###############################################################
#  Generated by:      Cadence Innovus 22.17-s086_1
#  OS:                Linux x86_64(Host ID vlsiktmt)
#  Generated on:      Mon Apr  6 12:51:59 2026
#  Design:            top_axi_ram
#  Command:           write_lef_abstract -noCutObs ./outputs/top_axi_ram.lef
###############################################################

VERSION 5.8 ;

BUSBITCHARS "[]" ;
DIVIDERCHAR "/" ;

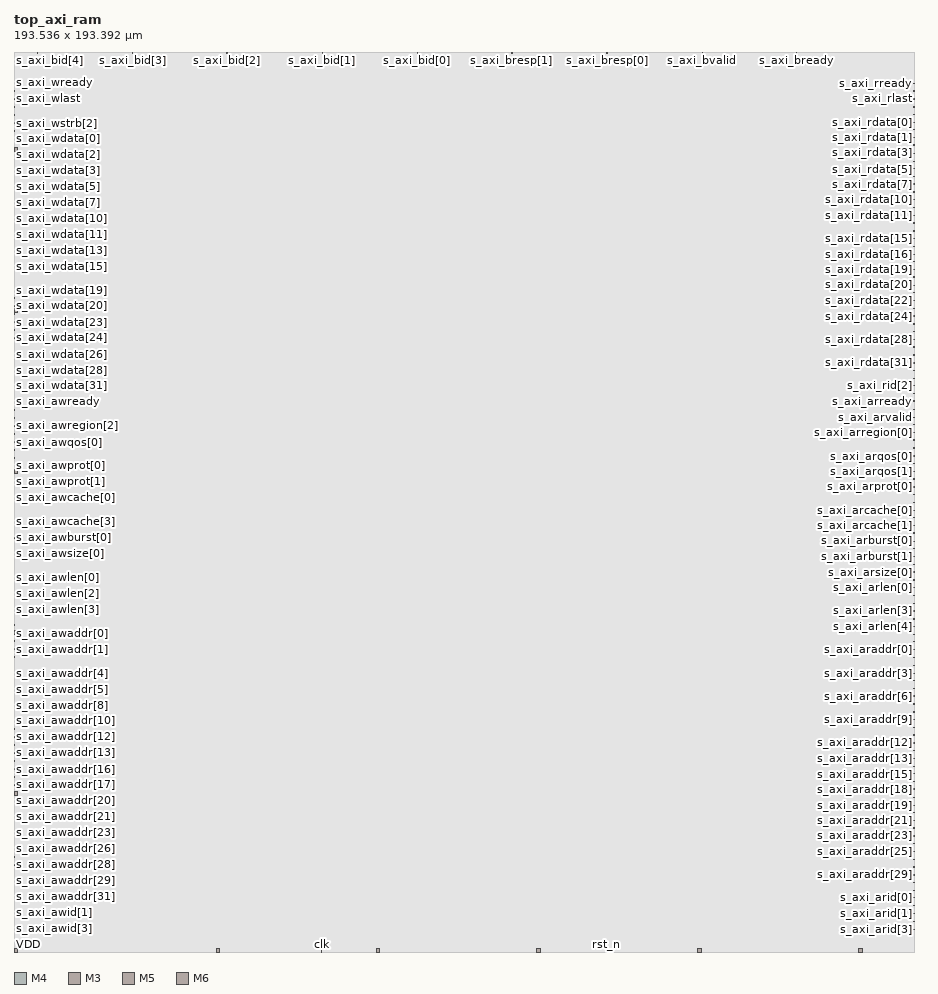
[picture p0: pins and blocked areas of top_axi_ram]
MACRO top_axi_ram
  CLASS BLOCK ;
  SIZE 193.536000 BY 193.392000 ;
  FOREIGN top_axi_ram 0.000000 0.000000 ;
  ORIGIN 0 0 ;
  SYMMETRY X Y R90 ;
  PIN clk
    DIRECTION INPUT ;
    USE SIGNAL ;
    PORT
      LAYER M4 ;
        RECT 66.048000 0.000000 66.144000 0.336000 ;
    END
  END clk
  PIN rst_n
    DIRECTION INPUT ;
    USE SIGNAL ;
    PORT
      LAYER M4 ;
        RECT 127.248000 0.000000 127.344000 0.336000 ;
    END
  END rst_n
  PIN s_axi_awid[4]
    DIRECTION INPUT ;
    USE SIGNAL ;
    PORT
      LAYER M3 ;
        RECT 0.000000 5.004000 0.148000 5.076000 ;
    END
  END s_axi_awid[4]
  PIN s_axi_awid[3]
    DIRECTION INPUT ;
    USE SIGNAL ;
    PORT
      LAYER M3 ;
        RECT 0.000000 6.732000 0.148000 6.804000 ;
    END
  END s_axi_awid[3]
  PIN s_axi_awid[2]
    DIRECTION INPUT ;
    USE SIGNAL ;
    PORT
      LAYER M3 ;
        RECT 0.000000 8.460000 0.148000 8.532000 ;
    END
  END s_axi_awid[2]
  PIN s_axi_awid[1]
    DIRECTION INPUT ;
    USE SIGNAL ;
    PORT
      LAYER M3 ;
        RECT 0.000000 10.188000 0.148000 10.260000 ;
    END
  END s_axi_awid[1]
  PIN s_axi_awid[0]
    DIRECTION INPUT ;
    USE SIGNAL ;
    PORT
      LAYER M3 ;
        RECT 0.000000 11.916000 0.148000 11.988000 ;
    END
  END s_axi_awid[0]
  PIN s_axi_awaddr[31]
    DIRECTION INPUT ;
    USE SIGNAL ;
    PORT
      LAYER M3 ;
        RECT 0.000000 13.644000 0.148000 13.716000 ;
    END
  END s_axi_awaddr[31]
  PIN s_axi_awaddr[30]
    DIRECTION INPUT ;
    USE SIGNAL ;
    PORT
      LAYER M3 ;
        RECT 0.000000 15.372000 0.148000 15.444000 ;
    END
  END s_axi_awaddr[30]
  PIN s_axi_awaddr[29]
    DIRECTION INPUT ;
    USE SIGNAL ;
    PORT
      LAYER M3 ;
        RECT 0.000000 17.100000 0.148000 17.172000 ;
    END
  END s_axi_awaddr[29]
  PIN s_axi_awaddr[28]
    DIRECTION INPUT ;
    USE SIGNAL ;
    PORT
      LAYER M3 ;
        RECT 0.000000 18.684000 0.148000 18.756000 ;
    END
  END s_axi_awaddr[28]
  PIN s_axi_awaddr[27]
    DIRECTION INPUT ;
    USE SIGNAL ;
    PORT
      LAYER M3 ;
        RECT 0.000000 20.412000 0.148000 20.484000 ;
    END
  END s_axi_awaddr[27]
  PIN s_axi_awaddr[26]
    DIRECTION INPUT ;
    USE SIGNAL ;
    PORT
      LAYER M3 ;
        RECT 0.000000 22.140000 0.148000 22.212000 ;
    END
  END s_axi_awaddr[26]
  PIN s_axi_awaddr[25]
    DIRECTION INPUT ;
    USE SIGNAL ;
    PORT
      LAYER M3 ;
        RECT 0.000000 23.868000 0.148000 23.940000 ;
    END
  END s_axi_awaddr[25]
  PIN s_axi_awaddr[24]
    DIRECTION INPUT ;
    USE SIGNAL ;
    PORT
      LAYER M3 ;
        RECT 0.000000 25.596000 0.148000 25.668000 ;
    END
  END s_axi_awaddr[24]
  PIN s_axi_awaddr[23]
    DIRECTION INPUT ;
    USE SIGNAL ;
    PORT
      LAYER M3 ;
        RECT 0.000000 27.324000 0.148000 27.396000 ;
    END
  END s_axi_awaddr[23]
  PIN s_axi_awaddr[22]
    DIRECTION INPUT ;
    USE SIGNAL ;
    PORT
      LAYER M3 ;
        RECT 0.000000 29.052000 0.148000 29.124000 ;
    END
  END s_axi_awaddr[22]
  PIN s_axi_awaddr[21]
    DIRECTION INPUT ;
    USE SIGNAL ;
    PORT
      LAYER M3 ;
        RECT 0.000000 30.780000 0.148000 30.852000 ;
    END
  END s_axi_awaddr[21]
  PIN s_axi_awaddr[20]
    DIRECTION INPUT ;
    USE SIGNAL ;
    PORT
      LAYER M3 ;
        RECT 0.000000 32.508000 0.148000 32.580000 ;
    END
  END s_axi_awaddr[20]
  PIN s_axi_awaddr[19]
    DIRECTION INPUT ;
    USE SIGNAL ;
    PORT
      LAYER M3 ;
        RECT 0.000000 34.236000 0.148000 34.308000 ;
    END
  END s_axi_awaddr[19]
  PIN s_axi_awaddr[18]
    DIRECTION INPUT ;
    USE SIGNAL ;
    PORT
      LAYER M3 ;
        RECT 0.000000 35.820000 0.148000 35.892000 ;
    END
  END s_axi_awaddr[18]
  PIN s_axi_awaddr[17]
    DIRECTION INPUT ;
    USE SIGNAL ;
    PORT
      LAYER M3 ;
        RECT 0.000000 37.548000 0.148000 37.620000 ;
    END
  END s_axi_awaddr[17]
  PIN s_axi_awaddr[16]
    DIRECTION INPUT ;
    USE SIGNAL ;
    PORT
      LAYER M3 ;
        RECT 0.000000 39.276000 0.148000 39.348000 ;
    END
  END s_axi_awaddr[16]
  PIN s_axi_awaddr[15]
    DIRECTION INPUT ;
    USE SIGNAL ;
    PORT
      LAYER M3 ;
        RECT 0.000000 41.004000 0.148000 41.076000 ;
    END
  END s_axi_awaddr[15]
  PIN s_axi_awaddr[14]
    DIRECTION INPUT ;
    USE SIGNAL ;
    PORT
      LAYER M3 ;
        RECT 0.000000 42.732000 0.148000 42.804000 ;
    END
  END s_axi_awaddr[14]
  PIN s_axi_awaddr[13]
    DIRECTION INPUT ;
    USE SIGNAL ;
    PORT
      LAYER M3 ;
        RECT 0.000000 44.460000 0.148000 44.532000 ;
    END
  END s_axi_awaddr[13]
  PIN s_axi_awaddr[12]
    DIRECTION INPUT ;
    USE SIGNAL ;
    PORT
      LAYER M3 ;
        RECT 0.000000 46.188000 0.148000 46.260000 ;
    END
  END s_axi_awaddr[12]
  PIN s_axi_awaddr[11]
    DIRECTION INPUT ;
    USE SIGNAL ;
    PORT
      LAYER M3 ;
        RECT 0.000000 47.916000 0.148000 47.988000 ;
    END
  END s_axi_awaddr[11]
  PIN s_axi_awaddr[10]
    DIRECTION INPUT ;
    USE SIGNAL ;
    PORT
      LAYER M3 ;
        RECT 0.000000 49.644000 0.148000 49.716000 ;
    END
  END s_axi_awaddr[10]
  PIN s_axi_awaddr[9]
    DIRECTION INPUT ;
    USE SIGNAL ;
    PORT
      LAYER M3 ;
        RECT 0.000000 51.372000 0.148000 51.444000 ;
    END
  END s_axi_awaddr[9]
  PIN s_axi_awaddr[8]
    DIRECTION INPUT ;
    USE SIGNAL ;
    PORT
      LAYER M3 ;
        RECT 0.000000 52.956000 0.148000 53.028000 ;
    END
  END s_axi_awaddr[8]
  PIN s_axi_awaddr[7]
    DIRECTION INPUT ;
    USE SIGNAL ;
    PORT
      LAYER M3 ;
        RECT 0.000000 54.684000 0.148000 54.756000 ;
    END
  END s_axi_awaddr[7]
  PIN s_axi_awaddr[6]
    DIRECTION INPUT ;
    USE SIGNAL ;
    PORT
      LAYER M3 ;
        RECT 0.000000 56.412000 0.148000 56.484000 ;
    END
  END s_axi_awaddr[6]
  PIN s_axi_awaddr[5]
    DIRECTION INPUT ;
    USE SIGNAL ;
    PORT
      LAYER M3 ;
        RECT 0.000000 58.140000 0.148000 58.212000 ;
    END
  END s_axi_awaddr[5]
  PIN s_axi_awaddr[4]
    DIRECTION INPUT ;
    USE SIGNAL ;
    PORT
      LAYER M3 ;
        RECT 0.000000 59.868000 0.148000 59.940000 ;
    END
  END s_axi_awaddr[4]
  PIN s_axi_awaddr[3]
    DIRECTION INPUT ;
    USE SIGNAL ;
    PORT
      LAYER M3 ;
        RECT 0.000000 61.596000 0.148000 61.668000 ;
    END
  END s_axi_awaddr[3]
  PIN s_axi_awaddr[2]
    DIRECTION INPUT ;
    USE SIGNAL ;
    PORT
      LAYER M3 ;
        RECT 0.000000 63.324000 0.148000 63.396000 ;
    END
  END s_axi_awaddr[2]
  PIN s_axi_awaddr[1]
    DIRECTION INPUT ;
    USE SIGNAL ;
    PORT
      LAYER M3 ;
        RECT 0.000000 65.052000 0.148000 65.124000 ;
    END
  END s_axi_awaddr[1]
  PIN s_axi_awaddr[0]
    DIRECTION INPUT ;
    USE SIGNAL ;
    PORT
      LAYER M3 ;
        RECT 0.000000 66.780000 0.148000 66.852000 ;
    END
  END s_axi_awaddr[0]
  PIN s_axi_awlen[7]
    DIRECTION INPUT ;
    USE SIGNAL ;
    PORT
      LAYER M3 ;
        RECT 0.000000 68.508000 0.148000 68.580000 ;
    END
  END s_axi_awlen[7]
  PIN s_axi_awlen[6]
    DIRECTION INPUT ;
    USE SIGNAL ;
    PORT
      LAYER M3 ;
        RECT 0.000000 70.236000 0.148000 70.308000 ;
    END
  END s_axi_awlen[6]
  PIN s_axi_awlen[5]
    DIRECTION INPUT ;
    USE SIGNAL ;
    PORT
      LAYER M3 ;
        RECT 0.000000 71.820000 0.148000 71.892000 ;
    END
  END s_axi_awlen[5]
  PIN s_axi_awlen[4]
    DIRECTION INPUT ;
    USE SIGNAL ;
    PORT
      LAYER M3 ;
        RECT 0.000000 73.548000 0.148000 73.620000 ;
    END
  END s_axi_awlen[4]
  PIN s_axi_awlen[3]
    DIRECTION INPUT ;
    USE SIGNAL ;
    PORT
      LAYER M3 ;
        RECT 0.000000 75.276000 0.148000 75.348000 ;
    END
  END s_axi_awlen[3]
  PIN s_axi_awlen[2]
    DIRECTION INPUT ;
    USE SIGNAL ;
    PORT
      LAYER M3 ;
        RECT 0.000000 77.004000 0.148000 77.076000 ;
    END
  END s_axi_awlen[2]
  PIN s_axi_awlen[1]
    DIRECTION INPUT ;
    USE SIGNAL ;
    PORT
      LAYER M3 ;
        RECT 0.000000 78.732000 0.148000 78.804000 ;
    END
  END s_axi_awlen[1]
  PIN s_axi_awlen[0]
    DIRECTION INPUT ;
    USE SIGNAL ;
    PORT
      LAYER M3 ;
        RECT 0.000000 80.460000 0.148000 80.532000 ;
    END
  END s_axi_awlen[0]
  PIN s_axi_awsize[2]
    DIRECTION INPUT ;
    USE SIGNAL ;
    PORT
      LAYER M3 ;
        RECT 0.000000 82.188000 0.148000 82.260000 ;
    END
  END s_axi_awsize[2]
  PIN s_axi_awsize[1]
    DIRECTION INPUT ;
    USE SIGNAL ;
    PORT
      LAYER M3 ;
        RECT 0.000000 83.916000 0.148000 83.988000 ;
    END
  END s_axi_awsize[1]
  PIN s_axi_awsize[0]
    DIRECTION INPUT ;
    USE SIGNAL ;
    PORT
      LAYER M3 ;
        RECT 0.000000 85.644000 0.148000 85.716000 ;
    END
  END s_axi_awsize[0]
  PIN s_axi_awburst[1]
    DIRECTION INPUT ;
    USE SIGNAL ;
    PORT
      LAYER M3 ;
        RECT 0.000000 87.372000 0.148000 87.444000 ;
    END
  END s_axi_awburst[1]
  PIN s_axi_awburst[0]
    DIRECTION INPUT ;
    USE SIGNAL ;
    PORT
      LAYER M3 ;
        RECT 0.000000 88.956000 0.148000 89.028000 ;
    END
  END s_axi_awburst[0]
  PIN s_axi_awlock
    DIRECTION INPUT ;
    USE SIGNAL ;
    PORT
      LAYER M3 ;
        RECT 0.000000 90.684000 0.148000 90.756000 ;
    END
  END s_axi_awlock
  PIN s_axi_awcache[3]
    DIRECTION INPUT ;
    USE SIGNAL ;
    PORT
      LAYER M3 ;
        RECT 0.000000 92.412000 0.148000 92.484000 ;
    END
  END s_axi_awcache[3]
  PIN s_axi_awcache[2]
    DIRECTION INPUT ;
    USE SIGNAL ;
    PORT
      LAYER M3 ;
        RECT 0.000000 94.140000 0.148000 94.212000 ;
    END
  END s_axi_awcache[2]
  PIN s_axi_awcache[1]
    DIRECTION INPUT ;
    USE SIGNAL ;
    PORT
      LAYER M3 ;
        RECT 0.000000 95.868000 0.148000 95.940000 ;
    END
  END s_axi_awcache[1]
  PIN s_axi_awcache[0]
    DIRECTION INPUT ;
    USE SIGNAL ;
    PORT
      LAYER M3 ;
        RECT 0.000000 97.596000 0.148000 97.668000 ;
    END
  END s_axi_awcache[0]
  PIN s_axi_awprot[2]
    DIRECTION INPUT ;
    USE SIGNAL ;
    PORT
      LAYER M3 ;
        RECT 0.000000 99.324000 0.148000 99.396000 ;
    END
  END s_axi_awprot[2]
  PIN s_axi_awprot[1]
    DIRECTION INPUT ;
    USE SIGNAL ;
    PORT
      LAYER M3 ;
        RECT 0.000000 101.052000 0.148000 101.124000 ;
    END
  END s_axi_awprot[1]
  PIN s_axi_awprot[0]
    DIRECTION INPUT ;
    USE SIGNAL ;
    PORT
      LAYER M3 ;
        RECT 0.000000 102.780000 0.148000 102.852000 ;
    END
  END s_axi_awprot[0]
  PIN s_axi_awqos[3]
    DIRECTION INPUT ;
    USE SIGNAL ;
    PORT
      LAYER M3 ;
        RECT 0.000000 104.508000 0.148000 104.580000 ;
    END
  END s_axi_awqos[3]
  PIN s_axi_awqos[2]
    DIRECTION INPUT ;
    USE SIGNAL ;
    PORT
      LAYER M3 ;
        RECT 0.000000 106.092000 0.148000 106.164000 ;
    END
  END s_axi_awqos[2]
  PIN s_axi_awqos[1]
    DIRECTION INPUT ;
    USE SIGNAL ;
    PORT
      LAYER M3 ;
        RECT 0.000000 107.820000 0.148000 107.892000 ;
    END
  END s_axi_awqos[1]
  PIN s_axi_awqos[0]
    DIRECTION INPUT ;
    USE SIGNAL ;
    PORT
      LAYER M3 ;
        RECT 0.000000 109.548000 0.148000 109.620000 ;
    END
  END s_axi_awqos[0]
  PIN s_axi_awregion[3]
    DIRECTION INPUT ;
    USE SIGNAL ;
    PORT
      LAYER M3 ;
        RECT 0.000000 111.276000 0.148000 111.348000 ;
    END
  END s_axi_awregion[3]
  PIN s_axi_awregion[2]
    DIRECTION INPUT ;
    USE SIGNAL ;
    PORT
      LAYER M3 ;
        RECT 0.000000 113.004000 0.148000 113.076000 ;
    END
  END s_axi_awregion[2]
  PIN s_axi_awregion[1]
    DIRECTION INPUT ;
    USE SIGNAL ;
    PORT
      LAYER M3 ;
        RECT 0.000000 114.732000 0.148000 114.804000 ;
    END
  END s_axi_awregion[1]
  PIN s_axi_awregion[0]
    DIRECTION INPUT ;
    USE SIGNAL ;
    PORT
      LAYER M3 ;
        RECT 0.000000 116.460000 0.148000 116.532000 ;
    END
  END s_axi_awregion[0]
  PIN s_axi_awvalid
    DIRECTION INPUT ;
    USE SIGNAL ;
    PORT
      LAYER M3 ;
        RECT 0.000000 118.188000 0.148000 118.260000 ;
    END
  END s_axi_awvalid
  PIN s_axi_awready
    DIRECTION OUTPUT ;
    USE SIGNAL ;
    PORT
      LAYER M3 ;
        RECT 0.000000 119.916000 0.148000 119.988000 ;
    END
  END s_axi_awready
  PIN s_axi_wdata[31]
    DIRECTION INPUT ;
    USE SIGNAL ;
    PORT
      LAYER M3 ;
        RECT 0.000000 121.644000 0.148000 121.716000 ;
    END
  END s_axi_wdata[31]
  PIN s_axi_wdata[30]
    DIRECTION INPUT ;
    USE SIGNAL ;
    PORT
      LAYER M3 ;
        RECT 0.000000 123.228000 0.148000 123.300000 ;
    END
  END s_axi_wdata[30]
  PIN s_axi_wdata[29]
    DIRECTION INPUT ;
    USE SIGNAL ;
    PORT
      LAYER M3 ;
        RECT 0.000000 124.956000 0.148000 125.028000 ;
    END
  END s_axi_wdata[29]
  PIN s_axi_wdata[28]
    DIRECTION INPUT ;
    USE SIGNAL ;
    PORT
      LAYER M3 ;
        RECT 0.000000 126.684000 0.148000 126.756000 ;
    END
  END s_axi_wdata[28]
  PIN s_axi_wdata[27]
    DIRECTION INPUT ;
    USE SIGNAL ;
    PORT
      LAYER M3 ;
        RECT 0.000000 128.412000 0.148000 128.484000 ;
    END
  END s_axi_wdata[27]
  PIN s_axi_wdata[26]
    DIRECTION INPUT ;
    USE SIGNAL ;
    PORT
      LAYER M3 ;
        RECT 0.000000 130.140000 0.148000 130.212000 ;
    END
  END s_axi_wdata[26]
  PIN s_axi_wdata[25]
    DIRECTION INPUT ;
    USE SIGNAL ;
    PORT
      LAYER M3 ;
        RECT 0.000000 131.868000 0.148000 131.940000 ;
    END
  END s_axi_wdata[25]
  PIN s_axi_wdata[24]
    DIRECTION INPUT ;
    USE SIGNAL ;
    PORT
      LAYER M3 ;
        RECT 0.000000 133.596000 0.148000 133.668000 ;
    END
  END s_axi_wdata[24]
  PIN s_axi_wdata[23]
    DIRECTION INPUT ;
    USE SIGNAL ;
    PORT
      LAYER M3 ;
        RECT 0.000000 135.324000 0.148000 135.396000 ;
    END
  END s_axi_wdata[23]
  PIN s_axi_wdata[22]
    DIRECTION INPUT ;
    USE SIGNAL ;
    PORT
      LAYER M3 ;
        RECT 0.000000 137.052000 0.148000 137.124000 ;
    END
  END s_axi_wdata[22]
  PIN s_axi_wdata[21]
    DIRECTION INPUT ;
    USE SIGNAL ;
    PORT
      LAYER M3 ;
        RECT 0.000000 138.780000 0.148000 138.852000 ;
    END
  END s_axi_wdata[21]
  PIN s_axi_wdata[20]
    DIRECTION INPUT ;
    USE SIGNAL ;
    PORT
      LAYER M3 ;
        RECT 0.000000 140.508000 0.148000 140.580000 ;
    END
  END s_axi_wdata[20]
  PIN s_axi_wdata[19]
    DIRECTION INPUT ;
    USE SIGNAL ;
    PORT
      LAYER M3 ;
        RECT 0.000000 142.092000 0.148000 142.164000 ;
    END
  END s_axi_wdata[19]
  PIN s_axi_wdata[18]
    DIRECTION INPUT ;
    USE SIGNAL ;
    PORT
      LAYER M3 ;
        RECT 0.000000 143.820000 0.148000 143.892000 ;
    END
  END s_axi_wdata[18]
  PIN s_axi_wdata[17]
    DIRECTION INPUT ;
    USE SIGNAL ;
    PORT
      LAYER M3 ;
        RECT 0.000000 145.548000 0.148000 145.620000 ;
    END
  END s_axi_wdata[17]
  PIN s_axi_wdata[16]
    DIRECTION INPUT ;
    USE SIGNAL ;
    PORT
      LAYER M3 ;
        RECT 0.000000 147.276000 0.148000 147.348000 ;
    END
  END s_axi_wdata[16]
  PIN s_axi_wdata[15]
    DIRECTION INPUT ;
    USE SIGNAL ;
    PORT
      LAYER M3 ;
        RECT 0.000000 149.004000 0.148000 149.076000 ;
    END
  END s_axi_wdata[15]
  PIN s_axi_wdata[14]
    DIRECTION INPUT ;
    USE SIGNAL ;
    PORT
      LAYER M3 ;
        RECT 0.000000 150.732000 0.148000 150.804000 ;
    END
  END s_axi_wdata[14]
  PIN s_axi_wdata[13]
    DIRECTION INPUT ;
    USE SIGNAL ;
    PORT
      LAYER M3 ;
        RECT 0.000000 152.460000 0.148000 152.532000 ;
    END
  END s_axi_wdata[13]
  PIN s_axi_wdata[12]
    DIRECTION INPUT ;
    USE SIGNAL ;
    PORT
      LAYER M3 ;
        RECT 0.000000 154.188000 0.148000 154.260000 ;
    END
  END s_axi_wdata[12]
  PIN s_axi_wdata[11]
    DIRECTION INPUT ;
    USE SIGNAL ;
    PORT
      LAYER M3 ;
        RECT 0.000000 155.916000 0.148000 155.988000 ;
    END
  END s_axi_wdata[11]
  PIN s_axi_wdata[10]
    DIRECTION INPUT ;
    USE SIGNAL ;
    PORT
      LAYER M3 ;
        RECT 0.000000 157.644000 0.148000 157.716000 ;
    END
  END s_axi_wdata[10]
  PIN s_axi_wdata[9]
    DIRECTION INPUT ;
    USE SIGNAL ;
    PORT
      LAYER M3 ;
        RECT 0.000000 159.228000 0.148000 159.300000 ;
    END
  END s_axi_wdata[9]
  PIN s_axi_wdata[8]
    DIRECTION INPUT ;
    USE SIGNAL ;
    PORT
      LAYER M3 ;
        RECT 0.000000 160.956000 0.148000 161.028000 ;
    END
  END s_axi_wdata[8]
  PIN s_axi_wdata[7]
    DIRECTION INPUT ;
    USE SIGNAL ;
    PORT
      LAYER M3 ;
        RECT 0.000000 162.684000 0.148000 162.756000 ;
    END
  END s_axi_wdata[7]
  PIN s_axi_wdata[6]
    DIRECTION INPUT ;
    USE SIGNAL ;
    PORT
      LAYER M3 ;
        RECT 0.000000 164.412000 0.148000 164.484000 ;
    END
  END s_axi_wdata[6]
  PIN s_axi_wdata[5]
    DIRECTION INPUT ;
    USE SIGNAL ;
    PORT
      LAYER M3 ;
        RECT 0.000000 166.140000 0.148000 166.212000 ;
    END
  END s_axi_wdata[5]
  PIN s_axi_wdata[4]
    DIRECTION INPUT ;
    USE SIGNAL ;
    PORT
      LAYER M3 ;
        RECT 0.000000 167.868000 0.148000 167.940000 ;
    END
  END s_axi_wdata[4]
  PIN s_axi_wdata[3]
    DIRECTION INPUT ;
    USE SIGNAL ;
    PORT
      LAYER M3 ;
        RECT 0.000000 169.596000 0.148000 169.668000 ;
    END
  END s_axi_wdata[3]
  PIN s_axi_wdata[2]
    DIRECTION INPUT ;
    USE SIGNAL ;
    PORT
      LAYER M3 ;
        RECT 0.000000 171.324000 0.148000 171.396000 ;
    END
  END s_axi_wdata[2]
  PIN s_axi_wdata[1]
    DIRECTION INPUT ;
    USE SIGNAL ;
    PORT
      LAYER M3 ;
        RECT 0.000000 173.052000 0.148000 173.124000 ;
    END
  END s_axi_wdata[1]
  PIN s_axi_wdata[0]
    DIRECTION INPUT ;
    USE SIGNAL ;
    PORT
      LAYER M3 ;
        RECT 0.000000 174.780000 0.148000 174.852000 ;
    END
  END s_axi_wdata[0]
  PIN s_axi_wstrb[3]
    DIRECTION INPUT ;
    USE SIGNAL ;
    PORT
      LAYER M3 ;
        RECT 0.000000 176.364000 0.148000 176.436000 ;
    END
  END s_axi_wstrb[3]
  PIN s_axi_wstrb[2]
    DIRECTION INPUT ;
    USE SIGNAL ;
    PORT
      LAYER M3 ;
        RECT 0.000000 178.092000 0.148000 178.164000 ;
    END
  END s_axi_wstrb[2]
  PIN s_axi_wstrb[1]
    DIRECTION INPUT ;
    USE SIGNAL ;
    PORT
      LAYER M3 ;
        RECT 0.000000 179.820000 0.148000 179.892000 ;
    END
  END s_axi_wstrb[1]
  PIN s_axi_wstrb[0]
    DIRECTION INPUT ;
    USE SIGNAL ;
    PORT
      LAYER M3 ;
        RECT 0.000000 181.548000 0.148000 181.620000 ;
    END
  END s_axi_wstrb[0]
  PIN s_axi_wlast
    DIRECTION INPUT ;
    USE SIGNAL ;
    PORT
      LAYER M3 ;
        RECT 0.000000 183.276000 0.148000 183.348000 ;
    END
  END s_axi_wlast
  PIN s_axi_wvalid
    DIRECTION INPUT ;
    USE SIGNAL ;
    PORT
      LAYER M3 ;
        RECT 0.000000 185.004000 0.148000 185.076000 ;
    END
  END s_axi_wvalid
  PIN s_axi_wready
    DIRECTION OUTPUT ;
    USE SIGNAL ;
    PORT
      LAYER M3 ;
        RECT 0.000000 186.732000 0.148000 186.804000 ;
    END
  END s_axi_wready
  PIN s_axi_bid[4]
    DIRECTION OUTPUT ;
    USE SIGNAL ;
    PORT
      LAYER M4 ;
        RECT 4.992000 193.056000 5.088000 193.392000 ;
    END
  END s_axi_bid[4]
  PIN s_axi_bid[3]
    DIRECTION OUTPUT ;
    USE SIGNAL ;
    PORT
      LAYER M4 ;
        RECT 25.440000 193.056000 25.536000 193.392000 ;
    END
  END s_axi_bid[3]
  PIN s_axi_bid[2]
    DIRECTION OUTPUT ;
    USE SIGNAL ;
    PORT
      LAYER M4 ;
        RECT 45.744000 193.056000 45.840000 193.392000 ;
    END
  END s_axi_bid[2]
  PIN s_axi_bid[1]
    DIRECTION OUTPUT ;
    USE SIGNAL ;
    PORT
      LAYER M4 ;
        RECT 66.192000 193.056000 66.288000 193.392000 ;
    END
  END s_axi_bid[1]
  PIN s_axi_bid[0]
    DIRECTION OUTPUT ;
    USE SIGNAL ;
    PORT
      LAYER M4 ;
        RECT 86.640000 193.056000 86.736000 193.392000 ;
    END
  END s_axi_bid[0]
  PIN s_axi_bresp[1]
    DIRECTION OUTPUT ;
    USE SIGNAL ;
    PORT
      LAYER M4 ;
        RECT 106.944000 193.056000 107.040000 193.392000 ;
    END
  END s_axi_bresp[1]
  PIN s_axi_bresp[0]
    DIRECTION OUTPUT ;
    USE SIGNAL ;
    PORT
      LAYER M4 ;
        RECT 127.392000 193.056000 127.488000 193.392000 ;
    END
  END s_axi_bresp[0]
  PIN s_axi_bvalid
    DIRECTION OUTPUT ;
    USE SIGNAL ;
    PORT
      LAYER M4 ;
        RECT 147.840000 193.056000 147.936000 193.392000 ;
    END
  END s_axi_bvalid
  PIN s_axi_bready
    DIRECTION INPUT ;
    USE SIGNAL ;
    PORT
      LAYER M4 ;
        RECT 168.144000 193.056000 168.240000 193.392000 ;
    END
  END s_axi_bready
  PIN s_axi_arid[4]
    DIRECTION INPUT ;
    USE SIGNAL ;
    PORT
      LAYER M3 ;
        RECT 193.388000 4.860000 193.536000 4.932000 ;
    END
  END s_axi_arid[4]
  PIN s_axi_arid[3]
    DIRECTION INPUT ;
    USE SIGNAL ;
    PORT
      LAYER M3 ;
        RECT 193.388000 6.588000 193.536000 6.660000 ;
    END
  END s_axi_arid[3]
  PIN s_axi_arid[2]
    DIRECTION INPUT ;
    USE SIGNAL ;
    PORT
      LAYER M3 ;
        RECT 193.388000 8.172000 193.536000 8.244000 ;
    END
  END s_axi_arid[2]
  PIN s_axi_arid[1]
    DIRECTION INPUT ;
    USE SIGNAL ;
    PORT
      LAYER M3 ;
        RECT 193.388000 9.900000 193.536000 9.972000 ;
    END
  END s_axi_arid[1]
  PIN s_axi_arid[0]
    DIRECTION INPUT ;
    USE SIGNAL ;
    PORT
      LAYER M3 ;
        RECT 193.388000 11.628000 193.536000 11.700000 ;
    END
  END s_axi_arid[0]
  PIN s_axi_araddr[31]
    DIRECTION INPUT ;
    USE SIGNAL ;
    PORT
      LAYER M3 ;
        RECT 193.388000 13.212000 193.536000 13.284000 ;
    END
  END s_axi_araddr[31]
  PIN s_axi_araddr[30]
    DIRECTION INPUT ;
    USE SIGNAL ;
    PORT
      LAYER M3 ;
        RECT 193.388000 14.940000 193.536000 15.012000 ;
    END
  END s_axi_araddr[30]
  PIN s_axi_araddr[29]
    DIRECTION INPUT ;
    USE SIGNAL ;
    PORT
      LAYER M3 ;
        RECT 193.388000 16.524000 193.536000 16.596000 ;
    END
  END s_axi_araddr[29]
  PIN s_axi_araddr[28]
    DIRECTION INPUT ;
    USE SIGNAL ;
    PORT
      LAYER M3 ;
        RECT 193.388000 18.252000 193.536000 18.324000 ;
    END
  END s_axi_araddr[28]
  PIN s_axi_araddr[27]
    DIRECTION INPUT ;
    USE SIGNAL ;
    PORT
      LAYER M3 ;
        RECT 193.388000 19.836000 193.536000 19.908000 ;
    END
  END s_axi_araddr[27]
  PIN s_axi_araddr[26]
    DIRECTION INPUT ;
    USE SIGNAL ;
    PORT
      LAYER M3 ;
        RECT 193.388000 21.564000 193.536000 21.636000 ;
    END
  END s_axi_araddr[26]
  PIN s_axi_araddr[25]
    DIRECTION INPUT ;
    USE SIGNAL ;
    PORT
      LAYER M3 ;
        RECT 193.388000 23.292000 193.536000 23.364000 ;
    END
  END s_axi_araddr[25]
  PIN s_axi_araddr[24]
    DIRECTION INPUT ;
    USE SIGNAL ;
    PORT
      LAYER M3 ;
        RECT 193.388000 24.876000 193.536000 24.948000 ;
    END
  END s_axi_araddr[24]
  PIN s_axi_araddr[23]
    DIRECTION INPUT ;
    USE SIGNAL ;
    PORT
      LAYER M3 ;
        RECT 193.388000 26.604000 193.536000 26.676000 ;
    END
  END s_axi_araddr[23]
  PIN s_axi_araddr[22]
    DIRECTION INPUT ;
    USE SIGNAL ;
    PORT
      LAYER M3 ;
        RECT 193.388000 28.188000 193.536000 28.260000 ;
    END
  END s_axi_araddr[22]
  PIN s_axi_araddr[21]
    DIRECTION INPUT ;
    USE SIGNAL ;
    PORT
      LAYER M3 ;
        RECT 193.388000 29.916000 193.536000 29.988000 ;
    END
  END s_axi_araddr[21]
  PIN s_axi_araddr[20]
    DIRECTION INPUT ;
    USE SIGNAL ;
    PORT
      LAYER M3 ;
        RECT 193.388000 31.500000 193.536000 31.572000 ;
    END
  END s_axi_araddr[20]
  PIN s_axi_araddr[19]
    DIRECTION INPUT ;
    USE SIGNAL ;
    PORT
      LAYER M3 ;
        RECT 193.388000 33.228000 193.536000 33.300000 ;
    END
  END s_axi_araddr[19]
  PIN s_axi_araddr[18]
    DIRECTION INPUT ;
    USE SIGNAL ;
    PORT
      LAYER M3 ;
        RECT 193.388000 34.956000 193.536000 35.028000 ;
    END
  END s_axi_araddr[18]
  PIN s_axi_araddr[17]
    DIRECTION INPUT ;
    USE SIGNAL ;
    PORT
      LAYER M3 ;
        RECT 193.388000 36.540000 193.536000 36.612000 ;
    END
  END s_axi_araddr[17]
  PIN s_axi_araddr[16]
    DIRECTION INPUT ;
    USE SIGNAL ;
    PORT
      LAYER M3 ;
        RECT 193.388000 38.268000 193.536000 38.340000 ;
    END
  END s_axi_araddr[16]
  PIN s_axi_araddr[15]
    DIRECTION INPUT ;
    USE SIGNAL ;
    PORT
      LAYER M3 ;
        RECT 193.388000 39.852000 193.536000 39.924000 ;
    END
  END s_axi_araddr[15]
  PIN s_axi_araddr[14]
    DIRECTION INPUT ;
    USE SIGNAL ;
    PORT
      LAYER M3 ;
        RECT 193.388000 41.580000 193.536000 41.652000 ;
    END
  END s_axi_araddr[14]
  PIN s_axi_araddr[13]
    DIRECTION INPUT ;
    USE SIGNAL ;
    PORT
      LAYER M3 ;
        RECT 193.388000 43.308000 193.536000 43.380000 ;
    END
  END s_axi_araddr[13]
  PIN s_axi_araddr[12]
    DIRECTION INPUT ;
    USE SIGNAL ;
    PORT
      LAYER M3 ;
        RECT 193.388000 44.892000 193.536000 44.964000 ;
    END
  END s_axi_araddr[12]
  PIN s_axi_araddr[11]
    DIRECTION INPUT ;
    USE SIGNAL ;
    PORT
      LAYER M3 ;
        RECT 193.388000 46.620000 193.536000 46.692000 ;
    END
  END s_axi_araddr[11]
  PIN s_axi_araddr[10]
    DIRECTION INPUT ;
    USE SIGNAL ;
    PORT
      LAYER M3 ;
        RECT 193.388000 48.204000 193.536000 48.276000 ;
    END
  END s_axi_araddr[10]
  PIN s_axi_araddr[9]
    DIRECTION INPUT ;
    USE SIGNAL ;
    PORT
      LAYER M3 ;
        RECT 193.388000 49.932000 193.536000 50.004000 ;
    END
  END s_axi_araddr[9]
  PIN s_axi_araddr[8]
    DIRECTION INPUT ;
    USE SIGNAL ;
    PORT
      LAYER M3 ;
        RECT 193.388000 51.516000 193.536000 51.588000 ;
    END
  END s_axi_araddr[8]
  PIN s_axi_araddr[7]
    DIRECTION INPUT ;
    USE SIGNAL ;
    PORT
      LAYER M3 ;
        RECT 193.388000 53.244000 193.536000 53.316000 ;
    END
  END s_axi_araddr[7]
  PIN s_axi_araddr[6]
    DIRECTION INPUT ;
    USE SIGNAL ;
    PORT
      LAYER M3 ;
        RECT 193.388000 54.972000 193.536000 55.044000 ;
    END
  END s_axi_araddr[6]
  PIN s_axi_araddr[5]
    DIRECTION INPUT ;
    USE SIGNAL ;
    PORT
      LAYER M3 ;
        RECT 193.388000 56.556000 193.536000 56.628000 ;
    END
  END s_axi_araddr[5]
  PIN s_axi_araddr[4]
    DIRECTION INPUT ;
    USE SIGNAL ;
    PORT
      LAYER M3 ;
        RECT 193.388000 58.284000 193.536000 58.356000 ;
    END
  END s_axi_araddr[4]
  PIN s_axi_araddr[3]
    DIRECTION INPUT ;
    USE SIGNAL ;
    PORT
      LAYER M3 ;
        RECT 193.388000 59.868000 193.536000 59.940000 ;
    END
  END s_axi_araddr[3]
  PIN s_axi_araddr[2]
    DIRECTION INPUT ;
    USE SIGNAL ;
    PORT
      LAYER M3 ;
        RECT 193.388000 61.596000 193.536000 61.668000 ;
    END
  END s_axi_araddr[2]
  PIN s_axi_araddr[1]
    DIRECTION INPUT ;
    USE SIGNAL ;
    PORT
      LAYER M3 ;
        RECT 193.388000 63.180000 193.536000 63.252000 ;
    END
  END s_axi_araddr[1]
  PIN s_axi_araddr[0]
    DIRECTION INPUT ;
    USE SIGNAL ;
    PORT
      LAYER M3 ;
        RECT 193.388000 64.908000 193.536000 64.980000 ;
    END
  END s_axi_araddr[0]
  PIN s_axi_arlen[7]
    DIRECTION INPUT ;
    USE SIGNAL ;
    PORT
      LAYER M3 ;
        RECT 193.388000 66.636000 193.536000 66.708000 ;
    END
  END s_axi_arlen[7]
  PIN s_axi_arlen[6]
    DIRECTION INPUT ;
    USE SIGNAL ;
    PORT
      LAYER M3 ;
        RECT 193.388000 68.220000 193.536000 68.292000 ;
    END
  END s_axi_arlen[6]
  PIN s_axi_arlen[5]
    DIRECTION INPUT ;
    USE SIGNAL ;
    PORT
      LAYER M3 ;
        RECT 193.388000 69.948000 193.536000 70.020000 ;
    END
  END s_axi_arlen[5]
  PIN s_axi_arlen[4]
    DIRECTION INPUT ;
    USE SIGNAL ;
    PORT
      LAYER M3 ;
        RECT 193.388000 71.532000 193.536000 71.604000 ;
    END
  END s_axi_arlen[4]
  PIN s_axi_arlen[3]
    DIRECTION INPUT ;
    USE SIGNAL ;
    PORT
      LAYER M3 ;
        RECT 193.388000 73.260000 193.536000 73.332000 ;
    END
  END s_axi_arlen[3]
  PIN s_axi_arlen[2]
    DIRECTION INPUT ;
    USE SIGNAL ;
    PORT
      LAYER M3 ;
        RECT 193.388000 74.844000 193.536000 74.916000 ;
    END
  END s_axi_arlen[2]
  PIN s_axi_arlen[1]
    DIRECTION INPUT ;
    USE SIGNAL ;
    PORT
      LAYER M3 ;
        RECT 193.388000 76.572000 193.536000 76.644000 ;
    END
  END s_axi_arlen[1]
  PIN s_axi_arlen[0]
    DIRECTION INPUT ;
    USE SIGNAL ;
    PORT
      LAYER M3 ;
        RECT 193.388000 78.300000 193.536000 78.372000 ;
    END
  END s_axi_arlen[0]
  PIN s_axi_arsize[2]
    DIRECTION INPUT ;
    USE SIGNAL ;
    PORT
      LAYER M3 ;
        RECT 193.388000 79.884000 193.536000 79.956000 ;
    END
  END s_axi_arsize[2]
  PIN s_axi_arsize[1]
    DIRECTION INPUT ;
    USE SIGNAL ;
    PORT
      LAYER M3 ;
        RECT 193.388000 81.612000 193.536000 81.684000 ;
    END
  END s_axi_arsize[1]
  PIN s_axi_arsize[0]
    DIRECTION INPUT ;
    USE SIGNAL ;
    PORT
      LAYER M3 ;
        RECT 193.388000 83.196000 193.536000 83.268000 ;
    END
  END s_axi_arsize[0]
  PIN s_axi_arburst[1]
    DIRECTION INPUT ;
    USE SIGNAL ;
    PORT
      LAYER M3 ;
        RECT 193.388000 84.924000 193.536000 84.996000 ;
    END
  END s_axi_arburst[1]
  PIN s_axi_arburst[0]
    DIRECTION INPUT ;
    USE SIGNAL ;
    PORT
      LAYER M3 ;
        RECT 193.388000 86.652000 193.536000 86.724000 ;
    END
  END s_axi_arburst[0]
  PIN s_axi_arlock
    DIRECTION INPUT ;
    USE SIGNAL ;
    PORT
      LAYER M3 ;
        RECT 193.388000 88.236000 193.536000 88.308000 ;
    END
  END s_axi_arlock
  PIN s_axi_arcache[3]
    DIRECTION INPUT ;
    USE SIGNAL ;
    PORT
      LAYER M3 ;
        RECT 193.388000 89.964000 193.536000 90.036000 ;
    END
  END s_axi_arcache[3]
  PIN s_axi_arcache[2]
    DIRECTION INPUT ;
    USE SIGNAL ;
    PORT
      LAYER M3 ;
        RECT 193.388000 91.548000 193.536000 91.620000 ;
    END
  END s_axi_arcache[2]
  PIN s_axi_arcache[1]
    DIRECTION INPUT ;
    USE SIGNAL ;
    PORT
      LAYER M3 ;
        RECT 193.388000 93.276000 193.536000 93.348000 ;
    END
  END s_axi_arcache[1]
  PIN s_axi_arcache[0]
    DIRECTION INPUT ;
    USE SIGNAL ;
    PORT
      LAYER M3 ;
        RECT 193.388000 94.860000 193.536000 94.932000 ;
    END
  END s_axi_arcache[0]
  PIN s_axi_arprot[2]
    DIRECTION INPUT ;
    USE SIGNAL ;
    PORT
      LAYER M3 ;
        RECT 193.388000 96.588000 193.536000 96.660000 ;
    END
  END s_axi_arprot[2]
  PIN s_axi_arprot[1]
    DIRECTION INPUT ;
    USE SIGNAL ;
    PORT
      LAYER M3 ;
        RECT 193.388000 98.316000 193.536000 98.388000 ;
    END
  END s_axi_arprot[1]
  PIN s_axi_arprot[0]
    DIRECTION INPUT ;
    USE SIGNAL ;
    PORT
      LAYER M3 ;
        RECT 193.388000 99.900000 193.536000 99.972000 ;
    END
  END s_axi_arprot[0]
  PIN s_axi_arqos[3]
    DIRECTION INPUT ;
    USE SIGNAL ;
    PORT
      LAYER M3 ;
        RECT 193.388000 101.628000 193.536000 101.700000 ;
    END
  END s_axi_arqos[3]
  PIN s_axi_arqos[2]
    DIRECTION INPUT ;
    USE SIGNAL ;
    PORT
      LAYER M3 ;
        RECT 193.388000 103.212000 193.536000 103.284000 ;
    END
  END s_axi_arqos[2]
  PIN s_axi_arqos[1]
    DIRECTION INPUT ;
    USE SIGNAL ;
    PORT
      LAYER M3 ;
        RECT 193.388000 104.940000 193.536000 105.012000 ;
    END
  END s_axi_arqos[1]
  PIN s_axi_arqos[0]
    DIRECTION INPUT ;
    USE SIGNAL ;
    PORT
      LAYER M3 ;
        RECT 193.388000 106.524000 193.536000 106.596000 ;
    END
  END s_axi_arqos[0]
  PIN s_axi_arregion[3]
    DIRECTION INPUT ;
    USE SIGNAL ;
    PORT
      LAYER M3 ;
        RECT 193.388000 108.252000 193.536000 108.324000 ;
    END
  END s_axi_arregion[3]
  PIN s_axi_arregion[2]
    DIRECTION INPUT ;
    USE SIGNAL ;
    PORT
      LAYER M3 ;
        RECT 193.388000 109.980000 193.536000 110.052000 ;
    END
  END s_axi_arregion[2]
  PIN s_axi_arregion[1]
    DIRECTION INPUT ;
    USE SIGNAL ;
    PORT
      LAYER M3 ;
        RECT 193.388000 111.564000 193.536000 111.636000 ;
    END
  END s_axi_arregion[1]
  PIN s_axi_arregion[0]
    DIRECTION INPUT ;
    USE SIGNAL ;
    PORT
      LAYER M3 ;
        RECT 193.388000 113.292000 193.536000 113.364000 ;
    END
  END s_axi_arregion[0]
  PIN s_axi_arvalid
    DIRECTION INPUT ;
    USE SIGNAL ;
    PORT
      LAYER M3 ;
        RECT 193.388000 114.876000 193.536000 114.948000 ;
    END
  END s_axi_arvalid
  PIN s_axi_arready
    DIRECTION OUTPUT ;
    USE SIGNAL ;
    PORT
      LAYER M3 ;
        RECT 193.388000 116.604000 193.536000 116.676000 ;
    END
  END s_axi_arready
  PIN s_axi_rid[4]
    DIRECTION OUTPUT ;
    USE SIGNAL ;
    PORT
      LAYER M3 ;
        RECT 193.388000 118.332000 193.536000 118.404000 ;
    END
  END s_axi_rid[4]
  PIN s_axi_rid[3]
    DIRECTION OUTPUT ;
    USE SIGNAL ;
    PORT
      LAYER M3 ;
        RECT 193.388000 119.916000 193.536000 119.988000 ;
    END
  END s_axi_rid[3]
  PIN s_axi_rid[2]
    DIRECTION OUTPUT ;
    USE SIGNAL ;
    PORT
      LAYER M3 ;
        RECT 193.388000 121.644000 193.536000 121.716000 ;
    END
  END s_axi_rid[2]
  PIN s_axi_rid[1]
    DIRECTION OUTPUT ;
    USE SIGNAL ;
    PORT
      LAYER M3 ;
        RECT 193.388000 123.228000 193.536000 123.300000 ;
    END
  END s_axi_rid[1]
  PIN s_axi_rid[0]
    DIRECTION OUTPUT ;
    USE SIGNAL ;
    PORT
      LAYER M3 ;
        RECT 193.388000 124.956000 193.536000 125.028000 ;
    END
  END s_axi_rid[0]
  PIN s_axi_rdata[31]
    DIRECTION OUTPUT ;
    USE SIGNAL ;
    PORT
      LAYER M3 ;
        RECT 193.388000 126.540000 193.536000 126.612000 ;
    END
  END s_axi_rdata[31]
  PIN s_axi_rdata[30]
    DIRECTION OUTPUT ;
    USE SIGNAL ;
    PORT
      LAYER M3 ;
        RECT 193.388000 128.268000 193.536000 128.340000 ;
    END
  END s_axi_rdata[30]
  PIN s_axi_rdata[29]
    DIRECTION OUTPUT ;
    USE SIGNAL ;
    PORT
      LAYER M3 ;
        RECT 193.388000 129.996000 193.536000 130.068000 ;
    END
  END s_axi_rdata[29]
  PIN s_axi_rdata[28]
    DIRECTION OUTPUT ;
    USE SIGNAL ;
    PORT
      LAYER M3 ;
        RECT 193.388000 131.580000 193.536000 131.652000 ;
    END
  END s_axi_rdata[28]
  PIN s_axi_rdata[27]
    DIRECTION OUTPUT ;
    USE SIGNAL ;
    PORT
      LAYER M3 ;
        RECT 193.388000 133.308000 193.536000 133.380000 ;
    END
  END s_axi_rdata[27]
  PIN s_axi_rdata[26]
    DIRECTION OUTPUT ;
    USE SIGNAL ;
    PORT
      LAYER M3 ;
        RECT 193.388000 134.892000 193.536000 134.964000 ;
    END
  END s_axi_rdata[26]
  PIN s_axi_rdata[25]
    DIRECTION OUTPUT ;
    USE SIGNAL ;
    PORT
      LAYER M3 ;
        RECT 193.388000 136.620000 193.536000 136.692000 ;
    END
  END s_axi_rdata[25]
  PIN s_axi_rdata[24]
    DIRECTION OUTPUT ;
    USE SIGNAL ;
    PORT
      LAYER M3 ;
        RECT 193.388000 138.204000 193.536000 138.276000 ;
    END
  END s_axi_rdata[24]
  PIN s_axi_rdata[23]
    DIRECTION OUTPUT ;
    USE SIGNAL ;
    PORT
      LAYER M3 ;
        RECT 193.388000 139.932000 193.536000 140.004000 ;
    END
  END s_axi_rdata[23]
  PIN s_axi_rdata[22]
    DIRECTION OUTPUT ;
    USE SIGNAL ;
    PORT
      LAYER M3 ;
        RECT 193.388000 141.660000 193.536000 141.732000 ;
    END
  END s_axi_rdata[22]
  PIN s_axi_rdata[21]
    DIRECTION OUTPUT ;
    USE SIGNAL ;
    PORT
      LAYER M3 ;
        RECT 193.388000 143.244000 193.536000 143.316000 ;
    END
  END s_axi_rdata[21]
  PIN s_axi_rdata[20]
    DIRECTION OUTPUT ;
    USE SIGNAL ;
    PORT
      LAYER M3 ;
        RECT 193.388000 144.972000 193.536000 145.044000 ;
    END
  END s_axi_rdata[20]
  PIN s_axi_rdata[19]
    DIRECTION OUTPUT ;
    USE SIGNAL ;
    PORT
      LAYER M3 ;
        RECT 193.388000 146.556000 193.536000 146.628000 ;
    END
  END s_axi_rdata[19]
  PIN s_axi_rdata[18]
    DIRECTION OUTPUT ;
    USE SIGNAL ;
    PORT
      LAYER M3 ;
        RECT 193.388000 148.284000 193.536000 148.356000 ;
    END
  END s_axi_rdata[18]
  PIN s_axi_rdata[17]
    DIRECTION OUTPUT ;
    USE SIGNAL ;
    PORT
      LAYER M3 ;
        RECT 193.388000 149.868000 193.536000 149.940000 ;
    END
  END s_axi_rdata[17]
  PIN s_axi_rdata[16]
    DIRECTION OUTPUT ;
    USE SIGNAL ;
    PORT
      LAYER M3 ;
        RECT 193.388000 151.596000 193.536000 151.668000 ;
    END
  END s_axi_rdata[16]
  PIN s_axi_rdata[15]
    DIRECTION OUTPUT ;
    USE SIGNAL ;
    PORT
      LAYER M3 ;
        RECT 193.388000 153.324000 193.536000 153.396000 ;
    END
  END s_axi_rdata[15]
  PIN s_axi_rdata[14]
    DIRECTION OUTPUT ;
    USE SIGNAL ;
    PORT
      LAYER M3 ;
        RECT 193.388000 154.908000 193.536000 154.980000 ;
    END
  END s_axi_rdata[14]
  PIN s_axi_rdata[13]
    DIRECTION OUTPUT ;
    USE SIGNAL ;
    PORT
      LAYER M3 ;
        RECT 193.388000 156.636000 193.536000 156.708000 ;
    END
  END s_axi_rdata[13]
  PIN s_axi_rdata[12]
    DIRECTION OUTPUT ;
    USE SIGNAL ;
    PORT
      LAYER M3 ;
        RECT 193.388000 158.220000 193.536000 158.292000 ;
    END
  END s_axi_rdata[12]
  PIN s_axi_rdata[11]
    DIRECTION OUTPUT ;
    USE SIGNAL ;
    PORT
      LAYER M3 ;
        RECT 193.388000 159.948000 193.536000 160.020000 ;
    END
  END s_axi_rdata[11]
  PIN s_axi_rdata[10]
    DIRECTION OUTPUT ;
    USE SIGNAL ;
    PORT
      LAYER M3 ;
        RECT 193.388000 161.676000 193.536000 161.748000 ;
    END
  END s_axi_rdata[10]
  PIN s_axi_rdata[9]
    DIRECTION OUTPUT ;
    USE SIGNAL ;
    PORT
      LAYER M3 ;
        RECT 193.388000 163.260000 193.536000 163.332000 ;
    END
  END s_axi_rdata[9]
  PIN s_axi_rdata[8]
    DIRECTION OUTPUT ;
    USE SIGNAL ;
    PORT
      LAYER M3 ;
        RECT 193.388000 164.988000 193.536000 165.060000 ;
    END
  END s_axi_rdata[8]
  PIN s_axi_rdata[7]
    DIRECTION OUTPUT ;
    USE SIGNAL ;
    PORT
      LAYER M3 ;
        RECT 193.388000 166.572000 193.536000 166.644000 ;
    END
  END s_axi_rdata[7]
  PIN s_axi_rdata[6]
    DIRECTION OUTPUT ;
    USE SIGNAL ;
    PORT
      LAYER M3 ;
        RECT 193.388000 168.300000 193.536000 168.372000 ;
    END
  END s_axi_rdata[6]
  PIN s_axi_rdata[5]
    DIRECTION OUTPUT ;
    USE SIGNAL ;
    PORT
      LAYER M3 ;
        RECT 193.388000 169.884000 193.536000 169.956000 ;
    END
  END s_axi_rdata[5]
  PIN s_axi_rdata[4]
    DIRECTION OUTPUT ;
    USE SIGNAL ;
    PORT
      LAYER M3 ;
        RECT 193.388000 171.612000 193.536000 171.684000 ;
    END
  END s_axi_rdata[4]
  PIN s_axi_rdata[3]
    DIRECTION OUTPUT ;
    USE SIGNAL ;
    PORT
      LAYER M3 ;
        RECT 193.388000 173.340000 193.536000 173.412000 ;
    END
  END s_axi_rdata[3]
  PIN s_axi_rdata[2]
    DIRECTION OUTPUT ;
    USE SIGNAL ;
    PORT
      LAYER M3 ;
        RECT 193.388000 174.924000 193.536000 174.996000 ;
    END
  END s_axi_rdata[2]
  PIN s_axi_rdata[1]
    DIRECTION OUTPUT ;
    USE SIGNAL ;
    PORT
      LAYER M3 ;
        RECT 193.388000 176.652000 193.536000 176.724000 ;
    END
  END s_axi_rdata[1]
  PIN s_axi_rdata[0]
    DIRECTION OUTPUT ;
    USE SIGNAL ;
    PORT
      LAYER M3 ;
        RECT 193.388000 178.236000 193.536000 178.308000 ;
    END
  END s_axi_rdata[0]
  PIN s_axi_rresp[1]
    DIRECTION OUTPUT ;
    USE SIGNAL ;
    PORT
      LAYER M3 ;
        RECT 193.388000 179.964000 193.536000 180.036000 ;
    END
  END s_axi_rresp[1]
  PIN s_axi_rresp[0]
    DIRECTION OUTPUT ;
    USE SIGNAL ;
    PORT
      LAYER M3 ;
        RECT 193.388000 181.548000 193.536000 181.620000 ;
    END
  END s_axi_rresp[0]
  PIN s_axi_rlast
    DIRECTION OUTPUT ;
    USE SIGNAL ;
    PORT
      LAYER M3 ;
        RECT 193.388000 183.276000 193.536000 183.348000 ;
    END
  END s_axi_rlast
  PIN s_axi_rvalid
    DIRECTION OUTPUT ;
    USE SIGNAL ;
    PORT
      LAYER M3 ;
        RECT 193.388000 185.004000 193.536000 185.076000 ;
    END
  END s_axi_rvalid
  PIN s_axi_rready
    DIRECTION INPUT ;
    USE SIGNAL ;
    PORT
      LAYER M3 ;
        RECT 193.388000 186.588000 193.536000 186.660000 ;
    END
  END s_axi_rready
  PIN VSS
    DIRECTION INOUT ;
    USE GROUND ;
    PORT
      LAYER M5 ;
        RECT 43.448000 0.000000 44.248000 0.800000 ;
    END
    PORT
      LAYER M5 ;
        RECT 77.792000 0.000000 78.592000 0.800000 ;
    END
    PORT
      LAYER M5 ;
        RECT 112.352000 0.000000 113.152000 0.800000 ;
    END
    PORT
      LAYER M5 ;
        RECT 146.912000 0.000000 147.712000 0.800000 ;
    END
    PORT
      LAYER M5 ;
        RECT 181.472000 0.000000 182.272000 0.800000 ;
    END
    PORT
      LAYER M6 ;
        RECT 0.000000 33.728000 0.800000 34.528000 ;
    END
    PORT
      LAYER M6 ;
        RECT 0.000000 68.288000 0.800000 69.088000 ;
    END
    PORT
      LAYER M6 ;
        RECT 0.000000 102.848000 0.800000 103.648000 ;
    END
    PORT
      LAYER M6 ;
        RECT 0.000000 137.408000 0.800000 138.208000 ;
    END
    PORT
      LAYER M6 ;
        RECT 0.000000 171.968000 0.800000 172.768000 ;
    END
    PORT
      LAYER M5 ;
        RECT 0.000000 0.000000 0.800000 0.800000 ;
    END
  END VSS
  PIN VDD
    DIRECTION INOUT ;
    USE POWER ;
    PORT
      LAYER M5 ;
        RECT 1.680000 1.680000 2.480000 2.480000 ;
    END
  END VDD
  OBS
    LAYER M1 ;
      RECT 0.000000 0.000000 193.536000 193.392000 ;
    LAYER M2 ;
      RECT 0.000000 0.000000 193.536000 193.392000 ;
    LAYER M3 ;
      RECT 0.000000 0.000000 193.536000 193.392000 ;
    LAYER M4 ;
      RECT 0.000000 0.000000 193.536000 193.392000 ;
    LAYER M5 ;
      RECT 0.000000 0.000000 193.536000 193.392000 ;
    LAYER M6 ;
      RECT 0.000000 0.000000 193.536000 193.392000 ;
    LAYER M7 ;
      RECT 0.000000 0.000000 193.536000 193.392000 ;
    LAYER M8 ;
      RECT 0.000000 0.000000 193.536000 193.392000 ;
    LAYER M9 ;
      RECT 0.000000 0.000000 193.536000 193.392000 ;
    LAYER Pad ;
      RECT 0.000000 0.000000 193.536000 193.392000 ;
  END
END top_axi_ram

END LIBRARY
